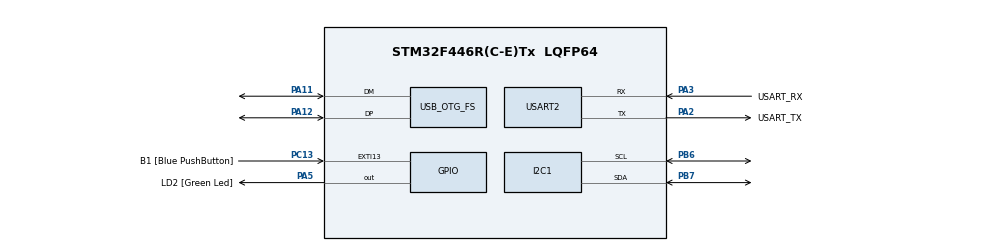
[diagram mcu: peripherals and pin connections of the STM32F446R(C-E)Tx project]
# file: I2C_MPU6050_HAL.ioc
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Mcu.Family=STM32F4
Mcu.Name=STM32F446R(C-E)Tx
Mcu.Package=LQFP64
NVIC.OTG_FS_IRQn=true\:0\:0\:false\:false\:true\:false\:true\:true
NVIC.PriorityGroup=NVIC_PRIORITYGROUP_0
PA11.Mode=Device_Only
PA11.Signal=USB_OTG_FS_DM
PA12.Mode=Device_Only
PA12.Signal=USB_OTG_FS_DP
PA13.GPIO_Label=TMS
PA13.Mode=Trace_Asynchronous_SW
PA13.Signal=SYS_JTMS-SWDIO
PA14.GPIO_Label=TCK
PA14.Mode=Trace_Asynchronous_SW
PA14.Signal=SYS_JTCK-SWCLK
PA2.GPIO_Label=USART_TX
PA2.Mode=Asynchronous
PA2.Signal=USART2_TX
PA3.GPIO_Label=USART_RX
PA3.Mode=Asynchronous
PA3.Signal=USART2_RX
PA5.GPIO_Label=LD2 [Green Led]
PA5.Signal=GPIO_Output
PB3.GPIO_Label=SWO
PB3.Mode=Trace_Asynchronous_SW
PB3.Signal=SYS_JTDO-SWO
PB6.Mode=I2C
PB6.Signal=I2C1_SCL
PB7.Mode=I2C
PB7.Signal=I2C1_SDA
PC13.GPIO_Label=B1 [Blue PushButton]
PC13.GPIO_ModeDefaultEXTI=GPIO_MODE_IT_FALLING
PC13.Signal=GPXTI13
PC14-OSC32_IN.Mode=LSE-External-Oscillator
PC14-OSC32_IN.Signal=RCC_OSC32_IN
PC15-OSC32_OUT.Mode=LSE-External-Oscillator
PC15-OSC32_OUT.Signal=RCC_OSC32_OUT
PH0-OSC_IN.Mode=HSE-External-Oscillator
PH0-OSC_IN.Signal=RCC_OSC_IN
PH1-OSC_OUT.Mode=HSE-External-Oscillator
PH1-OSC_OUT.Signal=RCC_OSC_OUT
ProjectManager.HeapSize=0x200
ProjectManager.StackSize=0x400
ProjectManager.TargetToolchain=STM32CubeIDE
RCC.48MHZClocksFreq_Value=84000000
RCC.AHBFreq_Value=96000000
RCC.APB1CLKDivider=RCC_HCLK_DIV4
RCC.APB1Freq_Value=24000000
RCC.APB1TimFreq_Value=48000000
RCC.APB2CLKDivider=RCC_HCLK_DIV2
RCC.APB2Freq_Value=48000000
RCC.APB2TimFreq_Value=96000000
RCC.CortexFreq_Value=96000000
RCC.FLatency-AdvancedSettings=FLASH_LATENCY_3
RCC.HCLKFreq_Value=96000000
RCC.HSE_VALUE=8000000
RCC.HSI_VALUE=16000000
RCC.PLLM=4
RCC.PLLP=RCC_PLLP_DIV4
RCC.PLLQ=8
RCC.SYSCLKFreq_VALUE=96000000
RCC.SYSCLKSource=RCC_SYSCLKSOURCE_PLLCLK
RCC.USBFreq_Value=48000000
RCC.VCOOutputFreq_Value=384000000
USART2.VirtualMode=VM_ASYNC
USB_DEVICE.CLASS_NAME_FS=CDC
USB_DEVICE.VirtualMode-CDC_FS=Cdc
USB_DEVICE.VirtualModeFS=Cdc_FS
USB_OTG_FS.VirtualMode=Device_Only
VP_USB_DEVICE_VS_USB_DEVICE_CDC_FS.Mode=CDC_FS
board=NUCLEO-F446RE

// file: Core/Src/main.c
/* USER CODE BEGIN Header */
/**
  ******************************************************************************
  * @file           : main.c
  * @brief          : Main program body
  ******************************************************************************
  * @attention
  *
  * Copyright (c) 2023 STMicroelectronics.
  * All rights reserved.
  *
  * This software is licensed under terms that can be found in the LICENSE file
  * in the root directory of this software component.
  * If no LICENSE file comes with this software, it is provided AS-IS.
  *
  ******************************************************************************
  */
/* USER CODE END Header */
#include "main.h"
#include "usb_device.h"
#include "usbd_cdc.h"
#include "usbd_cdc_if.h"

/* USER CODE BEGIN Includes */
#include "stdio.h"
#include "mpu6050.h"
#include "string.h"
/* USER CODE END Includes */

/* USER CODE BEGIN PD */
#define MPU6050_I2C_ADDR    0x68 << 1
/* USER CODE END PD */

I2C_HandleTypeDef hi2c1;

UART_HandleTypeDef huart2;

/* USER CODE BEGIN PV */
MPU6050_t MPU6050;

float floatAx;
float floatAy;
float floatAz;
/* USER CODE END PV */

void SystemClock_Config(void);
static void MX_GPIO_Init(void);
static void MX_USART2_UART_Init(void);
static void MX_I2C1_Init(void);

/* USER CODE BEGIN 0 */
int _write(int file, char *ptr, int len)
{
  (void)file;
  int DataIdx;

  for (DataIdx = 0; DataIdx < len; DataIdx++)
  {
    ITM_SendChar((*ptr++));
  }
  return len;
}
/* USER CODE END 0 */

int main(void)
{

  /* MCU Configuration--------------------------------------------------------*/

  /* Reset of all peripherals, Initializes the Flash interface and the Systick. */
  HAL_Init();

  /* Configure the system clock */
  SystemClock_Config();

  /* Initialize all configured peripherals */
  MX_GPIO_Init();
  MX_USART2_UART_Init();
  MX_I2C1_Init();
  /* USER CODE BEGIN 2 */
  HAL_StatusTypeDef ret =  HAL_I2C_IsDeviceReady(&hi2c1, MPU6050_I2C_ADDR, 1, 100);
  if(ret == HAL_OK)
  {
	  printf("The device is ready\n");
  }else
  {
	  printf("The device is not ready\n");
  }
  while (MPU6050_Init(&hi2c1) == 1);
  /* USER CODE END 2 */

  /* Infinite loop */
  while (1)
  {
	  MPU6050_Read_Accel(&hi2c1, &MPU6050);
	  floatAx = (float)MPU6050.Ax;
	  floatAy = (float)MPU6050.Ay;
	  floatAz = (float)MPU6050.Az;
	  char logbuf[120];
	  sprintf(logbuf, "%.4f, %.4f, %.4f\r\n", floatAx, floatAy, floatAz);
	  CDC_Transmit_FS((uint8_t*)logbuf, strlen(logbuf));
	  HAL_Delay (1);
  }
}

void SystemClock_Config(void)
{
  RCC_OscInitTypeDef RCC_OscInitStruct = {0};
  RCC_ClkInitTypeDef RCC_ClkInitStruct = {0};

  /** Configure the main internal regulator output voltage
  */
  __HAL_RCC_PWR_CLK_ENABLE();
  __HAL_PWR_VOLTAGESCALING_CONFIG(PWR_REGULATOR_VOLTAGE_SCALE3);

  /** Initializes the RCC Oscillators according to the specified parameters
  * in the RCC_OscInitTypeDef structure.
  */
  RCC_OscInitStruct.OscillatorType = RCC_OSCILLATORTYPE_HSI;
  RCC_OscInitStruct.HSIState = RCC_HSI_ON;
  RCC_OscInitStruct.HSICalibrationValue = RCC_HSICALIBRATION_DEFAULT;
  RCC_OscInitStruct.PLL.PLLState = RCC_PLL_ON;
  RCC_OscInitStruct.PLL.PLLSource = RCC_PLLSOURCE_HSI;
  RCC_OscInitStruct.PLL.PLLM = 16;
  RCC_OscInitStruct.PLL.PLLN = 336;
  RCC_OscInitStruct.PLL.PLLP = RCC_PLLP_DIV4;
  RCC_OscInitStruct.PLL.PLLQ = 2;
  RCC_OscInitStruct.PLL.PLLR = 2;
  if (HAL_RCC_OscConfig(&RCC_OscInitStruct) != HAL_OK)
  {
    Error_Handler();
  }

  /** Initializes the CPU, AHB and APB buses clocks
  */
  RCC_ClkInitStruct.ClockType = RCC_CLOCKTYPE_HCLK|RCC_CLOCKTYPE_SYSCLK
                              |RCC_CLOCKTYPE_PCLK1|RCC_CLOCKTYPE_PCLK2;
  RCC_ClkInitStruct.SYSCLKSource = RCC_SYSCLKSOURCE_PLLCLK;
  RCC_ClkInitStruct.AHBCLKDivider = RCC_SYSCLK_DIV1;
  RCC_ClkInitStruct.APB1CLKDivider = RCC_HCLK_DIV2;
  RCC_ClkInitStruct.APB2CLKDivider = RCC_HCLK_DIV1;

  if (HAL_RCC_ClockConfig(&RCC_ClkInitStruct, FLASH_LATENCY_2) != HAL_OK)
  {
    Error_Handler();
  }
}

static void MX_I2C1_Init(void)
{

  hi2c1.Instance = I2C1;
  hi2c1.Init.ClockSpeed = 100000;
  hi2c1.Init.DutyCycle = I2C_DUTYCYCLE_2;
  hi2c1.Init.OwnAddress1 = 0;
  hi2c1.Init.AddressingMode = I2C_ADDRESSINGMODE_7BIT;
  hi2c1.Init.DualAddressMode = I2C_DUALADDRESS_DISABLE;
  hi2c1.Init.OwnAddress2 = 0;
  hi2c1.Init.GeneralCallMode = I2C_GENERALCALL_DISABLE;
  hi2c1.Init.NoStretchMode = I2C_NOSTRETCH_DISABLE;
  if (HAL_I2C_Init(&hi2c1) != HAL_OK)
  {
    Error_Handler();
  }

}

static void MX_USART2_UART_Init(void)
{

  huart2.Instance = USART2;
  huart2.Init.BaudRate = 115200;
  huart2.Init.WordLength = UART_WORDLENGTH_8B;
  huart2.Init.StopBits = UART_STOPBITS_1;
  huart2.Init.Parity = UART_PARITY_NONE;
  huart2.Init.Mode = UART_MODE_TX_RX;
  huart2.Init.HwFlowCtl = UART_HWCONTROL_NONE;
  huart2.Init.OverSampling = UART_OVERSAMPLING_16;
  if (HAL_UART_Init(&huart2) != HAL_OK)
  {
    Error_Handler();
  }

}

static void MX_GPIO_Init(void)
{
  GPIO_InitTypeDef GPIO_InitStruct = {0};

  /* GPIO Ports Clock Enable */
  __HAL_RCC_GPIOC_CLK_ENABLE();
  __HAL_RCC_GPIOH_CLK_ENABLE();
  __HAL_RCC_GPIOA_CLK_ENABLE();
  __HAL_RCC_GPIOB_CLK_ENABLE();

  /*Configure GPIO pin Output Level */
  HAL_GPIO_WritePin(LD2_GPIO_Port, LD2_Pin, GPIO_PIN_RESET);

  /*Configure GPIO pin : B1_Pin */
  GPIO_InitStruct.Pin = B1_Pin;
  GPIO_InitStruct.Mode = GPIO_MODE_IT_FALLING;
  GPIO_InitStruct.Pull = GPIO_NOPULL;
  HAL_GPIO_Init(B1_GPIO_Port, &GPIO_InitStruct);

  /*Configure GPIO pin : LD2_Pin */
  GPIO_InitStruct.Pin = LD2_Pin;
  GPIO_InitStruct.Mode = GPIO_MODE_OUTPUT_PP;
  GPIO_InitStruct.Pull = GPIO_NOPULL;
  GPIO_InitStruct.Speed = GPIO_SPEED_FREQ_LOW;
  HAL_GPIO_Init(LD2_GPIO_Port, &GPIO_InitStruct);

}

void Error_Handler(void)
{
  __disable_irq();
  while (1)
  {
  }
}
